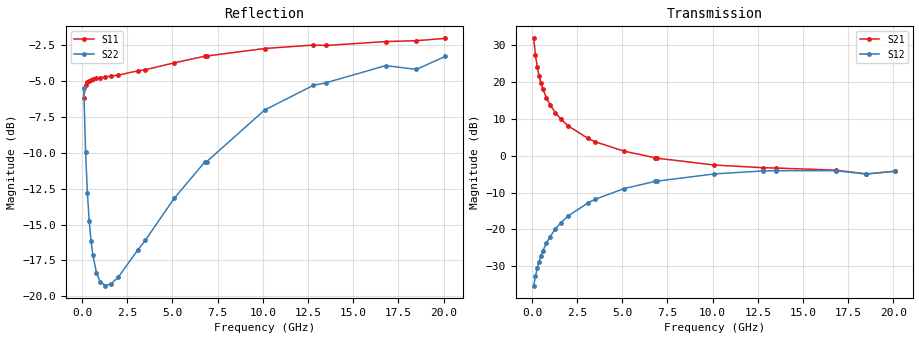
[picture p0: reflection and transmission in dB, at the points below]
!  Infineon Technologies AG
! BFR380L3 , PF131585-7, No.6, Th 09.10.01, soldered on pcb-board, measured with PP GSG850
!  Vce=2.5 V,  Ic=75.0 mA
! Common Emitter S-Parameters:  15. November 2001
#  GHz  S  MA  R  50
! f  S11  S21  S12  S22
! GHz  Mag  Ang  Mag  Ang  Mag  Ang  Mag  Ang
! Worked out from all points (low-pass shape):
!   201 points, 100 MHz to 20.1 GHz, reference 50 ohm
!   highest |S21| = 31.85 dB at 100 MHz (marker M1); lowest = -4.9 dB at 18.5 GHz (marker M2)
!   |S21| within 3 dB of the highest: start of sweep to 164.6 MHz
!   lowest |S11| = -6.2 dB at 100 MHz (marker M3), VSWR 2.93, Z = 22.1 - j24.9 ohm
!   |S11| at or under -10 dB: nowhere
!   |S22| runs from -19.2 to -3.3 dB; largest |S21 - S12| = 39
!   S11 on the Smith chart (normalised r, x): 100 MHz: 0.44, -0.50; 500 MHz: 0.28, -0.06; 3.1 GHz: 0.27, +0.34; 6.9 GHz: 0.32, +0.82; 12.8 GHz: 0.53, +1.56; 20.1 GHz: 1.03, +2.60
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0.1  0.4907 -119.2  39.13 126.1  0.01727 56.9  0.5283 -57.5
0.2  0.5429 -148.6  22.92 108.0  0.0234 58.3  0.3184 -79.1
0.3  0.5556 -161.0  15.87 100.0  0.02987 61.6  0.2292 -90.4
0.4  0.5632 -168.0  12.08 94.9  0.03655 64.5  0.1832 -98.7
0.5  0.567 -172.7  9.734 91.2  0.04364 67.2  0.1564 -105.1
0.6  0.5688 -176.4  8.144 88.3  0.05071 68.6  0.1397 -110.5
0.8  0.5724 177.9  6.151 83.5  0.06514 70.2  0.1211 -119.2
1  0.575 173.0  4.949 79.4  0.07949 70.8  0.1126 -126.0
1.3  0.5792 167.2  3.836 74.0  0.1014 70.4  0.109 -133.8
1.6  0.5837 161.9  3.145 68.9  0.1233 69.3  0.1106 -139.9
2  0.5878 155.7  2.549 62.8  0.152 67.4  0.1165 -146.5
3.1  0.6088 139.9  1.721 47.4  0.2291 60.4  0.1454 -161.5
3.5  0.6137 134.6  1.548 42.3  0.2567 57.6  0.1566 -165.5
5.1  0.6486 115.9  1.154 24.7  0.3584 45.7  0.2193 175.0
6.8  0.6844 98.9  0.941 10.4  0.4484 33.4  0.2936 154.7
6.9  0.6851 97.9  0.9282 9.7  0.452 32.5  0.2942 153.7
10.1  0.7275 74.5  0.7484 -8.6  0.5673 10.9  0.4445 123.8
12.8  0.748 61.2  0.6884 -20.2  0.6226 -6.1  0.5419 101.2
13.5  0.7455 57.8  0.6812 -22.7  0.6271 -10.1  0.5532 96.7
16.8  0.7691 46.2  0.6385 -33.8  0.6278 -25.9  0.6344 75.9
18.5  0.7745 44.2  0.5673 -40.7  0.5641 -34.1  0.6156 70.7
20.1  0.7891 37.3  0.616 -44.3  0.6185 -39.4  0.6833 60.1
